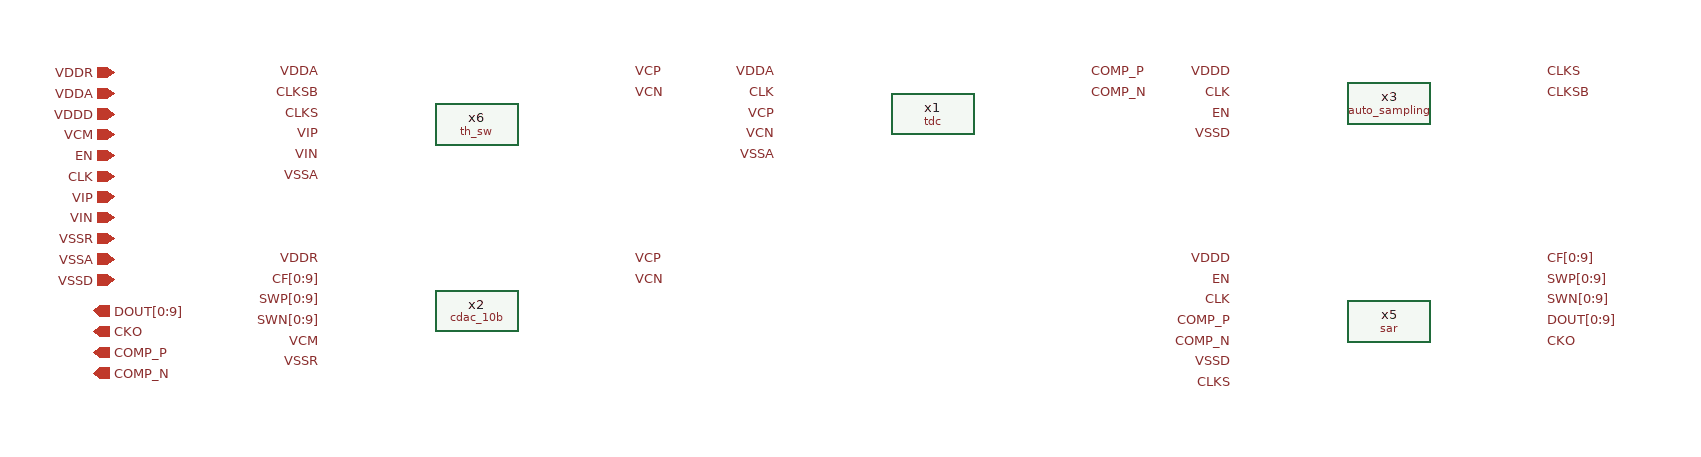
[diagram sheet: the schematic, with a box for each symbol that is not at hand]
v {xschem version=3.4.5 file_version=1.2
}
G {}
K {}
V {}
S {}
E {}
C {devices/lab_wire.sym} 300 -330 0 0 {name=p1 sig_type=std_logic lab=VDDA}
C {devices/lab_wire.sym} 300 -150 0 0 {name=p2 sig_type=std_logic lab=VDDR}
C {devices/lab_wire.sym} 740 -330 0 0 {name=p3 sig_type=std_logic lab=VDDA}
C {devices/lab_wire.sym} 740 -250 0 0 {name=p4 sig_type=std_logic lab=VSSA}
C {devices/lab_wire.sym} 300 -50 0 0 {name=p5 sig_type=std_logic lab=VSSR}
C {devices/lab_wire.sym} 300 -230 0 0 {name=p6 sig_type=std_logic lab=VSSA}
C {devices/lab_wire.sym} 1180 -150 0 0 {name=p7 sig_type=std_logic lab=VDDD}
C {devices/lab_wire.sym} 1180 -50 0 0 {name=p8 sig_type=std_logic lab=VSSD}
C {devices/lab_wire.sym} 300 -290 0 0 {name=p9 sig_type=std_logic lab=CLKS}
C {devices/lab_wire.sym} 300 -310 0 0 {name=p10 sig_type=std_logic lab=CLKSB}
C {devices/lab_wire.sym} 1180 -30 0 0 {name=p11 sig_type=std_logic lab=CLKS}
C {devices/lab_wire.sym} 1180 -70 0 0 {name=p15 sig_type=std_logic lab=COMP_N}
C {devices/lab_wire.sym} 1180 -110 0 0 {name=p17 sig_type=std_logic lab=CLK}
C {devices/lab_wire.sym} 600 -330 0 1 {name=p18 sig_type=std_logic lab=VCP}
C {devices/lab_wire.sym} 600 -310 0 1 {name=p19 sig_type=std_logic lab=VCN}
C {devices/lab_wire.sym} 600 -150 0 1 {name=p20 sig_type=std_logic lab=VCP}
C {devices/lab_wire.sym} 600 -130 0 1 {name=p21 sig_type=std_logic lab=VCN}
C {devices/lab_wire.sym} 740 -290 0 0 {name=p22 sig_type=std_logic lab=VCP}
C {devices/lab_wire.sym} 740 -270 0 0 {name=p23 sig_type=std_logic lab=VCN}
C {devices/lab_wire.sym} 740 -310 0 0 {name=p25 sig_type=std_logic lab=CLK}
C {devices/lab_wire.sym} 300 -70 0 0 {name=p26 sig_type=std_logic lab=VCM}
C {devices/lab_wire.sym} 300 -270 0 0 {name=p27 sig_type=std_logic lab=VIP}
C {devices/lab_wire.sym} 300 -250 0 0 {name=p28 sig_type=std_logic lab=VIN}
C {devices/lab_wire.sym} 300 -130 0 0 {name=p29 sig_type=std_logic lab=CF[0:9]}
C {devices/lab_wire.sym} 300 -110 0 0 {name=p30 sig_type=std_logic lab=SWP[0:9]}
C {devices/lab_wire.sym} 300 -90 0 0 {name=p31 sig_type=std_logic lab=SWN[0:9]}
C {devices/lab_wire.sym} 1480 -150 0 1 {name=p32 sig_type=std_logic lab=CF[0:9]}
C {devices/lab_wire.sym} 1480 -130 0 1 {name=p33 sig_type=std_logic lab=SWP[0:9]}
C {devices/lab_wire.sym} 1480 -110 0 1 {name=p34 sig_type=std_logic lab=SWN[0:9]}
C {devices/lab_wire.sym} 1480 -70 0 1 {name=p35 sig_type=std_logic lab=CKO}
C {devices/lab_wire.sym} 1480 -90 0 1 {name=p36 sig_type=std_logic lab=DOUT[0:9]}
C {devices/ipin.sym} 100 -310 0 0 {name=p37 sig_type=std_logic lab=VDDA}
C {devices/ipin.sym} 100 -290 0 0 {name=p38 sig_type=std_logic lab=VDDD}
C {devices/ipin.sym} 100 -270 0 0 {name=p39 sig_type=std_logic lab=VCM}
C {devices/ipin.sym} 100 -230 0 0 {name=p40 sig_type=std_logic lab=CLK}
C {devices/ipin.sym} 100 -210 0 0 {name=p41 sig_type=std_logic lab=VIP}
C {devices/ipin.sym} 100 -190 0 0 {name=p42 sig_type=std_logic lab=VIN}
C {devices/ipin.sym} 100 -150 0 0 {name=p43 sig_type=std_logic lab=VSSA}
C {devices/ipin.sym} 100 -130 0 0 {name=p44 sig_type=std_logic lab=VSSD}
C {devices/opin.sym} 80 -100 0 0 {name=p45 sig_type=std_logic lab=DOUT[0:9]}
C {devices/opin.sym} 80 -80 0 0 {name=p46 sig_type=std_logic lab=CKO}
C {devices/ipin.sym} 100 -170 0 0 {name=p14 sig_type=std_logic lab=VSSR}
C {devices/ipin.sym} 100 -330 0 0 {name=p16 sig_type=std_logic lab=VDDR}
C {devices/lab_wire.sym} 1180 -90 0 0 {name=p24 sig_type=std_logic lab=COMP_P}
C {devices/lab_wire.sym} 1040 -330 0 1 {name=p13 sig_type=std_logic lab=COMP_P}
C {devices/lab_wire.sym} 1040 -310 0 1 {name=p48 sig_type=std_logic lab=COMP_N}
C {devices/lab_wire.sym} 1180 -130 0 0 {name=p47 sig_type=std_logic lab=EN}
C {devices/ipin.sym} 100 -250 0 0 {name=p49 sig_type=std_logic lab=EN}
C {devices/opin.sym} 80 -60 0 0 {name=p50 sig_type=std_logic lab=COMP_P}
C {devices/opin.sym} 80 -40 0 0 {name=p51 sig_type=std_logic lab=COMP_N}
C {devices/lab_wire.sym} 1180 -330 0 0 {name=p52 sig_type=std_logic lab=VDDD}
C {devices/lab_wire.sym} 1180 -270 0 0 {name=p53 sig_type=std_logic lab=VSSD}
C {devices/lab_wire.sym} 1180 -310 0 0 {name=p54 sig_type=std_logic lab=CLK}
C {devices/lab_wire.sym} 1480 -330 0 1 {name=p55 sig_type=std_logic lab=CLKS}
C {devices/lab_wire.sym} 1480 -310 0 1 {name=p56 sig_type=std_logic lab=CLKSB}
C {devices/lab_wire.sym} 1180 -290 0 0 {name=p57 sig_type=std_logic lab=EN}
C {/foss/designs/th_sw.sym} 450 -280 0 0 {name=x6}
C {/foss/designs/cdac_10b.sym} 450 -100 0 0 {name=x2}
C {/foss/designs/tdc.sym} 890 -290 0 0 {name=x1}
C {/foss/designs/auto_sampling.sym} 1330 -300 0 0 {name=x3}
C {/foss/designs/sar.sym} 1330 -90 0 0 {name=x5}
